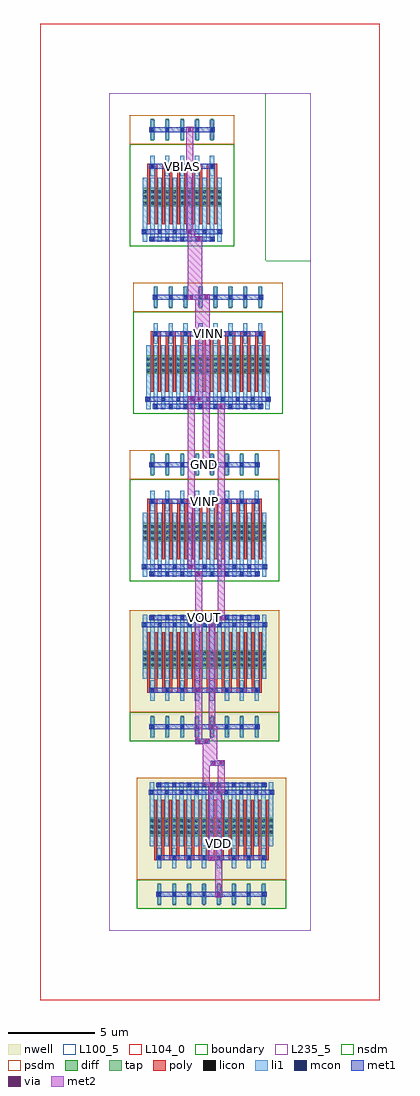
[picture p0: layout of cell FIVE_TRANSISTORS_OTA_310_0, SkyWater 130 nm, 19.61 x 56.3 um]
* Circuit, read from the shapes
.subckt FIVE_TRANSISTORS_OTA_310_0 GND VBIAS VDD VINN VINP VOUT
XM1 n1 VINP n2 GND sky130_fd_pr__nfet_01v8 w=1.05 l=0.15 m=16
XM2 n2 VBIAS GND GND sky130_fd_pr__nfet_01v8 w=1.05 l=0.15 m=10
XM3 VOUT VINN n2 GND sky130_fd_pr__nfet_01v8 w=1.05 l=0.15 m=16
XM4 VOUT n1 VDD VDD sky130_fd_pr__pfet_01v8 w=1.05 l=0.15 m=16
XM5 n1 n1 VDD VDD sky130_fd_pr__pfet_01v8 w=1.05 l=0.15 m=16
.ends

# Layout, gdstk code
import gdstk
lib = gdstk.Library(unit=1e-6, precision=1e-09)
def R(c, l, rs):  # rectangles x0, y0, x1, y1
    for r in rs: c.add(gdstk.rectangle(r[:2], r[2:], *l))
def A(c, l, x, y, w, h, nx, ny, dx, dy):  # array of equal rectangles
    R(c, l, [(x+i*dx, y+j*dy, x+i*dx+w, y+j*dy+h) for i in range(nx) for j in range(ny)])
def P(c, l, *ps):  # polygons
    for p in ps: c.add(gdstk.Polygon(p, *l))
nwell = (64, 20)
diff = (65, 20)
tap = (65, 44)
poly = (66, 20)
licon = (66, 44)
li1 = (67, 20)
mcon = (67, 44)
met1 = (68, 20)
via = (68, 44)
met2 = (69, 20)
nsdm = (93, 44)
psdm = (94, 20)
L100_5 = (100, 5)
L104_0 = (104, 0)
boundary = (235, 4)
L235_5 = (235, 5)

dcl_pmos_s_17530687_x8_y = lib.new_cell('DCL_PMOS_S_17530687_X8_Y1_1746753567')
R(dcl_pmos_s_17530687_x8_y, nwell, [(1.59,0.84,10.19,8.4)])
R(dcl_pmos_s_17530687_x8_y, diff, [(2.325,3.15,9.455,4.2)])
A(dcl_pmos_s_17530687_x8_y, tap, 2.795, 6.915, 0.17, 1.29, 8, 1, 0.86, 0)
A(dcl_pmos_s_17530687_x8_y, poly, 2.59, 2.1, 0.15, 3.36, 16, 1, 0.43, 0)
A(dcl_pmos_s_17530687_x8_y, poly, 2.59, 5.325, 0.58, 0.27, 8, 1, 0.86, 0)
A(dcl_pmos_s_17530687_x8_y, licon, 2.365, 3.23, 0.17, 0.17, 3, 3, 0.43, 0.34)
A(dcl_pmos_s_17530687_x8_y, licon, 3.225, 3.23, 0.17, 0.17, 3, 3, 0.43, 0.34)
A(dcl_pmos_s_17530687_x8_y, licon, 4.085, 3.23, 0.17, 0.17, 3, 3, 0.43, 0.34)
A(dcl_pmos_s_17530687_x8_y, licon, 4.945, 3.23, 0.17, 0.17, 3, 3, 0.43, 0.34)
A(dcl_pmos_s_17530687_x8_y, licon, 5.805, 3.23, 0.17, 0.17, 3, 3, 0.43, 0.34)
A(dcl_pmos_s_17530687_x8_y, licon, 6.665, 3.23, 0.17, 0.17, 3, 3, 0.43, 0.34)
A(dcl_pmos_s_17530687_x8_y, licon, 7.525, 3.23, 0.17, 0.17, 3, 3, 0.43, 0.34)
A(dcl_pmos_s_17530687_x8_y, licon, 8.385, 3.23, 0.17, 0.17, 3, 3, 0.43, 0.34)
A(dcl_pmos_s_17530687_x8_y, licon, 2.795, 5.375, 0.17, 0.17, 8, 2, 0.86, 2.1)
A(dcl_pmos_s_17530687_x8_y, li1, 2.325, 1.09, 0.25, 3.7, 17, 1, 0.43, 0)
A(dcl_pmos_s_17530687_x8_y, li1, 2.755, 4.87, 0.25, 1.18, 8, 2, 0.86, 2.1)
A(dcl_pmos_s_17530687_x8_y, mcon, 2.795, 1.175, 0.17, 0.17, 8, 2, 0.86, 4.2)
A(dcl_pmos_s_17530687_x8_y, mcon, 2.365, 1.595, 0.17, 0.17, 9, 1, 0.86, 0)
A(dcl_pmos_s_17530687_x8_y, mcon, 2.795, 7.475, 0.17, 0.17, 8, 1, 0.86, 0)
R(dcl_pmos_s_17530687_x8_y, met1, [(2.71,1.12,9.07,1.4), (2.28,1.54,9.5,1.82), (2.71,5.32,9.07,5.6), (2.71,7.42,9.07,7.7)])
R(dcl_pmos_s_17530687_x8_y, via, [(5.815,1.185,5.965,1.335), (6.245,1.605,6.395,1.755), (5.815,5.385,5.965,5.535), (6.245,7.485,6.395,7.635)])
R(dcl_pmos_s_17530687_x8_y, met2, [(5.69,1.1,6.09,5.62), (6.12,1.52,6.52,7.72)])
R(dcl_pmos_s_17530687_x8_y, nsdm, [(1.59,6.72,10.19,8.4)])
R(dcl_pmos_s_17530687_x8_y, psdm, [(1.59,0.84,10.19,6.72)])
R(dcl_pmos_s_17530687_x8_y, L100_5, [(0,0,11.61,9.66)])
R(dcl_pmos_s_17530687_x8_y, boundary, [(0,0,11.61,9.66)])

nmos_s_52209288_x5_y1_17 = lib.new_cell('NMOS_S_52209288_X5_Y1_1746753570')
R(nmos_s_52209288_x5_y1_17, diff, [(1.925,3.15,6.475,4.2)])
A(nmos_s_52209288_x5_y1_17, tap, 2.395, 6.915, 0.17, 1.29, 5, 1, 0.86, 0)
A(nmos_s_52209288_x5_y1_17, poly, 2.19, 2.1, 0.15, 3.36, 10, 1, 0.43, 0)
A(nmos_s_52209288_x5_y1_17, poly, 2.19, 5.325, 0.58, 0.27, 5, 1, 0.86, 0)
A(nmos_s_52209288_x5_y1_17, licon, 1.965, 3.23, 0.17, 0.17, 3, 3, 0.43, 0.34)
A(nmos_s_52209288_x5_y1_17, licon, 2.825, 3.23, 0.17, 0.17, 3, 3, 0.43, 0.34)
A(nmos_s_52209288_x5_y1_17, licon, 3.685, 3.23, 0.17, 0.17, 3, 3, 0.43, 0.34)
A(nmos_s_52209288_x5_y1_17, licon, 4.545, 3.23, 0.17, 0.17, 3, 3, 0.43, 0.34)
A(nmos_s_52209288_x5_y1_17, licon, 5.405, 3.23, 0.17, 0.17, 3, 3, 0.43, 0.34)
A(nmos_s_52209288_x5_y1_17, licon, 2.395, 5.375, 0.17, 0.17, 5, 2, 0.86, 2.1)
A(nmos_s_52209288_x5_y1_17, li1, 1.925, 1.09, 0.25, 3.7, 11, 1, 0.43, 0)
A(nmos_s_52209288_x5_y1_17, li1, 2.355, 4.87, 0.25, 1.18, 5, 2, 0.86, 2.1)
A(nmos_s_52209288_x5_y1_17, mcon, 2.395, 1.175, 0.17, 0.17, 5, 2, 0.86, 4.2)
A(nmos_s_52209288_x5_y1_17, mcon, 1.965, 1.595, 0.17, 0.17, 6, 1, 0.86, 0)
A(nmos_s_52209288_x5_y1_17, mcon, 2.395, 7.475, 0.17, 0.17, 5, 1, 0.86, 0)
R(nmos_s_52209288_x5_y1_17, met1, [(2.31,1.12,6.09,1.4), (1.88,1.54,6.52,1.82), (2.31,5.32,6.09,5.6), (2.31,7.42,6.09,7.7)])
R(nmos_s_52209288_x5_y1_17, via, [(4.555,1.605,4.705,1.755), (4.555,7.485,4.705,7.635)])
R(nmos_s_52209288_x5_y1_17, met2, [(4.43,1.52,4.83,7.72)])
R(nmos_s_52209288_x5_y1_17, nsdm, [(1.19,0.84,7.21,6.72)])
R(nmos_s_52209288_x5_y1_17, psdm, [(1.19,6.72,7.21,8.4)])
R(nmos_s_52209288_x5_y1_17, L100_5, [(0,0,9.03,9.66)])
R(nmos_s_52209288_x5_y1_17, boundary, [(0,0,9.03,9.66)])

pmos_s_93182587_x8_y1_17 = lib.new_cell('PMOS_S_93182587_X8_Y1_1746753571')
R(pmos_s_93182587_x8_y1_17, nwell, [(1.19,0.84,9.79,8.4)])
R(pmos_s_93182587_x8_y1_17, diff, [(1.925,3.15,9.055,4.2)])
A(pmos_s_93182587_x8_y1_17, tap, 2.395, 6.915, 0.17, 1.29, 8, 1, 0.86, 0)
A(pmos_s_93182587_x8_y1_17, poly, 2.19, 2.1, 0.15, 3.36, 16, 1, 0.43, 0)
A(pmos_s_93182587_x8_y1_17, poly, 2.19, 5.325, 0.58, 0.27, 8, 1, 0.86, 0)
A(pmos_s_93182587_x8_y1_17, licon, 1.965, 3.23, 0.17, 0.17, 3, 3, 0.43, 0.34)
A(pmos_s_93182587_x8_y1_17, licon, 2.825, 3.23, 0.17, 0.17, 3, 3, 0.43, 0.34)
A(pmos_s_93182587_x8_y1_17, licon, 3.685, 3.23, 0.17, 0.17, 3, 3, 0.43, 0.34)
A(pmos_s_93182587_x8_y1_17, licon, 4.545, 3.23, 0.17, 0.17, 3, 3, 0.43, 0.34)
A(pmos_s_93182587_x8_y1_17, licon, 5.405, 3.23, 0.17, 0.17, 3, 3, 0.43, 0.34)
A(pmos_s_93182587_x8_y1_17, licon, 6.265, 3.23, 0.17, 0.17, 3, 3, 0.43, 0.34)
A(pmos_s_93182587_x8_y1_17, licon, 7.125, 3.23, 0.17, 0.17, 3, 3, 0.43, 0.34)
A(pmos_s_93182587_x8_y1_17, licon, 7.985, 3.23, 0.17, 0.17, 3, 3, 0.43, 0.34)
A(pmos_s_93182587_x8_y1_17, licon, 2.395, 5.375, 0.17, 0.17, 8, 2, 0.86, 2.1)
A(pmos_s_93182587_x8_y1_17, li1, 1.925, 1.09, 0.25, 3.7, 17, 1, 0.43, 0)
A(pmos_s_93182587_x8_y1_17, li1, 2.355, 4.87, 0.25, 1.18, 8, 2, 0.86, 2.1)
A(pmos_s_93182587_x8_y1_17, mcon, 2.395, 1.175, 0.17, 0.17, 8, 2, 0.86, 4.2)
A(pmos_s_93182587_x8_y1_17, mcon, 1.965, 1.595, 0.17, 0.17, 9, 1, 0.86, 0)
A(pmos_s_93182587_x8_y1_17, mcon, 2.395, 7.475, 0.17, 0.17, 8, 1, 0.86, 0)
R(pmos_s_93182587_x8_y1_17, met1, [(2.31,1.12,8.67,1.4), (1.88,1.54,9.1,1.82), (2.31,5.32,8.67,5.6), (2.31,7.42,8.67,7.7)])
R(pmos_s_93182587_x8_y1_17, via, [(5.845,1.605,5.995,1.755), (5.845,7.485,5.995,7.635)])
R(pmos_s_93182587_x8_y1_17, met2, [(5.72,1.52,6.12,7.72)])
R(pmos_s_93182587_x8_y1_17, nsdm, [(1.19,6.72,9.79,8.4)])
R(pmos_s_93182587_x8_y1_17, psdm, [(1.19,0.84,9.79,6.72)])
R(pmos_s_93182587_x8_y1_17, L100_5, [(0,0,11.61,9.66)])
R(pmos_s_93182587_x8_y1_17, boundary, [(0,0,11.61,9.66)])

nmos_4t_3160949_x8_y1_17 = lib.new_cell('NMOS_4T_3160949_X8_Y1_1746753569')
R(nmos_4t_3160949_x8_y1_17, diff, [(2.125,3.15,9.255,4.2)])
A(nmos_4t_3160949_x8_y1_17, tap, 2.595, 6.915, 0.17, 1.29, 8, 1, 0.86, 0)
A(nmos_4t_3160949_x8_y1_17, poly, 2.39, 2.1, 0.15, 3.36, 16, 1, 0.43, 0)
A(nmos_4t_3160949_x8_y1_17, poly, 2.39, 5.325, 0.58, 0.27, 8, 1, 0.86, 0)
A(nmos_4t_3160949_x8_y1_17, licon, 2.165, 3.23, 0.17, 0.17, 3, 3, 0.43, 0.34)
A(nmos_4t_3160949_x8_y1_17, licon, 3.025, 3.23, 0.17, 0.17, 3, 3, 0.43, 0.34)
A(nmos_4t_3160949_x8_y1_17, licon, 3.885, 3.23, 0.17, 0.17, 3, 3, 0.43, 0.34)
A(nmos_4t_3160949_x8_y1_17, licon, 4.745, 3.23, 0.17, 0.17, 3, 3, 0.43, 0.34)
A(nmos_4t_3160949_x8_y1_17, licon, 5.605, 3.23, 0.17, 0.17, 3, 3, 0.43, 0.34)
A(nmos_4t_3160949_x8_y1_17, licon, 6.465, 3.23, 0.17, 0.17, 3, 3, 0.43, 0.34)
A(nmos_4t_3160949_x8_y1_17, licon, 7.325, 3.23, 0.17, 0.17, 3, 3, 0.43, 0.34)
A(nmos_4t_3160949_x8_y1_17, licon, 8.185, 3.23, 0.17, 0.17, 3, 3, 0.43, 0.34)
A(nmos_4t_3160949_x8_y1_17, licon, 2.595, 5.375, 0.17, 0.17, 8, 2, 0.86, 2.1)
A(nmos_4t_3160949_x8_y1_17, li1, 2.125, 1.09, 0.25, 3.7, 17, 1, 0.43, 0)
A(nmos_4t_3160949_x8_y1_17, li1, 2.555, 4.87, 0.25, 1.18, 8, 2, 0.86, 2.1)
A(nmos_4t_3160949_x8_y1_17, mcon, 2.595, 1.175, 0.17, 0.17, 8, 2, 0.86, 4.2)
A(nmos_4t_3160949_x8_y1_17, mcon, 2.165, 1.595, 0.17, 0.17, 9, 1, 0.86, 0)
A(nmos_4t_3160949_x8_y1_17, mcon, 2.595, 7.475, 0.17, 0.17, 8, 1, 0.86, 0)
R(nmos_4t_3160949_x8_y1_17, met1, [(2.51,1.12,8.87,1.4), (2.08,1.54,9.3,1.82), (2.51,5.32,8.87,5.6), (2.51,7.42,8.87,7.7)])
R(nmos_4t_3160949_x8_y1_17, nsdm, [(1.39,0.84,9.99,6.72)])
R(nmos_4t_3160949_x8_y1_17, psdm, [(1.39,6.72,9.99,8.4)])
R(nmos_4t_3160949_x8_y1_17, L100_5, [(0,0,11.61,9.66)])
R(nmos_4t_3160949_x8_y1_17, boundary, [(0,0,11.61,9.66)])

nmos_4t_21140221_x8_y1_1 = lib.new_cell('NMOS_4T_21140221_X8_Y1_1746753568')
R(nmos_4t_21140221_x8_y1_1, diff, [(1.925,3.15,9.055,4.2)])
A(nmos_4t_21140221_x8_y1_1, tap, 2.395, 6.915, 0.17, 1.29, 8, 1, 0.86, 0)
A(nmos_4t_21140221_x8_y1_1, poly, 2.19, 2.1, 0.15, 3.36, 16, 1, 0.43, 0)
A(nmos_4t_21140221_x8_y1_1, poly, 2.19, 5.325, 0.58, 0.27, 8, 1, 0.86, 0)
A(nmos_4t_21140221_x8_y1_1, licon, 1.965, 3.23, 0.17, 0.17, 3, 3, 0.43, 0.34)
A(nmos_4t_21140221_x8_y1_1, licon, 2.825, 3.23, 0.17, 0.17, 3, 3, 0.43, 0.34)
A(nmos_4t_21140221_x8_y1_1, licon, 3.685, 3.23, 0.17, 0.17, 3, 3, 0.43, 0.34)
A(nmos_4t_21140221_x8_y1_1, licon, 4.545, 3.23, 0.17, 0.17, 3, 3, 0.43, 0.34)
A(nmos_4t_21140221_x8_y1_1, licon, 5.405, 3.23, 0.17, 0.17, 3, 3, 0.43, 0.34)
A(nmos_4t_21140221_x8_y1_1, licon, 6.265, 3.23, 0.17, 0.17, 3, 3, 0.43, 0.34)
A(nmos_4t_21140221_x8_y1_1, licon, 7.125, 3.23, 0.17, 0.17, 3, 3, 0.43, 0.34)
A(nmos_4t_21140221_x8_y1_1, licon, 7.985, 3.23, 0.17, 0.17, 3, 3, 0.43, 0.34)
A(nmos_4t_21140221_x8_y1_1, licon, 2.395, 5.375, 0.17, 0.17, 8, 2, 0.86, 2.1)
A(nmos_4t_21140221_x8_y1_1, li1, 1.925, 1.09, 0.25, 3.7, 17, 1, 0.43, 0)
A(nmos_4t_21140221_x8_y1_1, li1, 2.355, 4.87, 0.25, 1.18, 8, 2, 0.86, 2.1)
A(nmos_4t_21140221_x8_y1_1, mcon, 2.395, 1.175, 0.17, 0.17, 8, 2, 0.86, 4.2)
A(nmos_4t_21140221_x8_y1_1, mcon, 1.965, 1.595, 0.17, 0.17, 9, 1, 0.86, 0)
A(nmos_4t_21140221_x8_y1_1, mcon, 2.395, 7.475, 0.17, 0.17, 8, 1, 0.86, 0)
R(nmos_4t_21140221_x8_y1_1, met1, [(2.31,1.12,8.67,1.4), (1.88,1.54,9.1,1.82), (2.31,5.32,8.67,5.6), (2.31,7.42,8.67,7.7)])
R(nmos_4t_21140221_x8_y1_1, nsdm, [(1.19,0.84,9.79,6.72)])
R(nmos_4t_21140221_x8_y1_1, psdm, [(1.19,6.72,9.79,8.4)])
R(nmos_4t_21140221_x8_y1_1, L100_5, [(0,0,11.61,9.66)])
R(nmos_4t_21140221_x8_y1_1, boundary, [(0,0,11.61,9.66)])

five_transistors_ota_310 = lib.new_cell('FIVE_TRANSISTORS_OTA_310_0')
R(five_transistors_ota_310, met1, [(5.86,9.52,6.18,9.8), (5.86,9.52,6.18,9.8), (6.02,9.52,6.45,9.8), (6.29,9.52,6.61,9.8), (6.29,9.52,6.61,9.8), (5,10.78,5.32,11.06), (5,10.78,5.32,11.06), (5,10.78,5.32,11.06), (5,10.78,5.32,11.06), (5.16,10.78,5.59,11.06), (5.43,10.78,5.75,11.06), (5.43,10.78,5.75,11.06), (5.43,10.78,5.75,11.06), (5.43,10.78,5.75,11.06), (5,13.72,5.32,14), (5,13.72,5.32,14), (5,13.72,5.32,14), (5,13.72,5.32,14), (6.29,17.92,6.61,18.2), (6.29,17.92,6.61,18.2), (5,20.44,5.32,20.72), (5,20.44,5.32,20.72), (4.57,20.86,4.89,21.14), (4.57,20.86,4.89,21.14), (4.57,20.86,4.89,21.14), (4.57,20.86,4.89,21.14), (5.43,26.74,5.75,27.02), (5.43,26.74,5.75,27.02), (5.43,26.74,5.75,27.02), (5.43,26.74,5.75,27.02), (6.29,30.1,6.61,30.38), (6.29,30.1,6.61,30.38), (4.57,30.52,4.89,30.8), (4.57,30.52,4.89,30.8), (4.57,30.52,4.89,30.8), (4.57,30.52,4.89,30.8), (5,30.52,5.32,30.8), (5,30.52,5.32,30.8), (4.57,36.4,4.89,36.68), (4.57,36.4,4.89,36.68), (5.43,36.4,5.75,36.68), (5.43,36.4,5.75,36.68), (5.43,36.4,5.75,36.68), (5.43,36.4,5.75,36.68), (5,39.76,5.32,40.04), (5,39.76,5.32,40.04)])
P(five_transistors_ota_310, met1, [(0,0),(0,0),(0,0),(0,0)],
  [(0,0),(0,0),(0,0),(0,0)],
  [(0,0),(0,0),(0,0),(0,0)],
  [(0,0),(0,0),(0,0),(0,0)],
  [(0,0),(0,0),(0,0),(0,0)],
  [(0,0),(0,0),(0,0),(0,0)],
  [(0,0),(0,0),(0,0),(0,0)],
  [(0,0),(0,0),(0,0),(0,0)],
  [(0,0),(0,0),(0,0),(0,0)],
  [(0,0),(0,0),(0,0),(0,0)],
  [(0,0),(0,0),(0,0),(0,0)],
  [(0,0),(0,0),(0,0),(0,0)],
  [(0,0),(0,0),(0,0),(0,0)],
  [(0,0),(0,0),(0,0),(0,0)],
  [(0,0),(0,0),(0,0),(0,0)],
  [(0,0),(0,0),(0,0),(0,0)],
  [(0,0),(0,0),(0,0),(0,0)])
R(five_transistors_ota_310, via, [(5.945,9.585,6.095,9.735), (5.945,9.585,6.095,9.735), (6.375,9.585,6.525,9.735), (6.375,9.585,6.525,9.735), (5.085,10.845,5.235,10.995), (5.085,10.845,5.235,10.995), (5.085,10.845,5.235,10.995), (5.085,10.845,5.235,10.995), (5.515,10.845,5.665,10.995), (5.515,10.845,5.665,10.995), (5.515,10.845,5.665,10.995), (5.515,10.845,5.665,10.995), (5.085,13.785,5.235,13.935), (5.085,13.785,5.235,13.935), (5.085,13.785,5.235,13.935), (5.085,13.785,5.235,13.935), (6.375,17.985,6.525,18.135), (6.375,17.985,6.525,18.135), (5.085,20.505,5.235,20.655), (5.085,20.505,5.235,20.655), (4.655,20.925,4.805,21.075), (4.655,20.925,4.805,21.075), (4.655,20.925,4.805,21.075), (4.655,20.925,4.805,21.075), (5.515,26.805,5.665,26.955), (5.515,26.805,5.665,26.955), (5.515,26.805,5.665,26.955), (5.515,26.805,5.665,26.955), (6.375,30.165,6.525,30.315), (6.375,30.165,6.525,30.315), (4.655,30.585,4.805,30.735), (4.655,30.585,4.805,30.735), (4.655,30.585,4.805,30.735), (4.655,30.585,4.805,30.735), (5.085,30.585,5.235,30.735), (5.085,30.585,5.235,30.735), (4.655,36.465,4.805,36.615), (4.655,36.465,4.805,36.615), (5.515,36.465,5.665,36.615), (5.515,36.465,5.665,36.615), (5.515,36.465,5.665,36.615), (5.515,36.465,5.665,36.615), (5.085,39.825,5.235,39.975), (5.085,39.825,5.235,39.975)])
R(five_transistors_ota_310, met2, [(6.25,7.98,6.65,9.66), (5.39,8.4,5.79,10.92), (5.82,9.5,6.22,9.82), (5.82,9.5,6.22,9.82), (6.25,9.5,6.65,9.82), (6.25,9.5,6.65,9.82), (5.82,9.66,6.22,11.76), (4.96,10.76,5.36,11.08), (4.96,10.76,5.36,11.08), (4.96,10.76,5.36,11.08), (4.96,10.76,5.36,11.08), (5.39,10.76,5.79,11.08), (5.39,10.76,5.79,11.08), (5.39,10.76,5.79,11.08), (5.39,10.76,5.79,11.08), (4.96,10.92,5.36,13.86), (4.96,13.7,5.36,14.02), (4.96,13.7,5.36,14.02), (4.96,13.7,5.36,14.02), (4.96,13.7,5.36,14.02), (4.96,13.86,5.36,20.58), (6.25,17.9,6.65,18.22), (6.25,17.9,6.65,18.22), (6.25,18.06,6.65,30.24), (4.96,20.42,5.36,20.74), (4.96,20.42,5.36,20.74), (4.53,20.84,4.93,21.16), (4.53,20.84,4.93,21.16), (4.53,20.84,4.93,21.16), (4.53,20.84,4.93,21.16), (4.53,21,4.93,30.66), (5.39,26.72,5.79,27.04), (5.39,26.72,5.79,27.04), (5.39,26.72,5.79,27.04), (5.39,26.72,5.79,27.04), (5.39,26.88,5.79,36.54), (6.25,30.08,6.65,30.4), (6.25,30.08,6.65,30.4), (4.53,30.5,4.93,30.82), (4.53,30.5,4.93,30.82), (4.53,30.5,4.93,30.82), (4.53,30.5,4.93,30.82), (4.96,30.5,5.36,30.82), (4.96,30.5,5.36,30.82), (4.96,30.66,5.36,39.9), (4.53,36.38,4.93,36.7), (4.53,36.38,4.93,36.7), (5.39,36.38,5.79,36.7), (5.39,36.38,5.79,36.7), (5.39,36.38,5.79,36.7), (5.39,36.38,5.79,36.7), (4.53,36.54,4.93,40.32), (4.96,39.74,5.36,40.06), (4.96,39.74,5.36,40.06)])
P(five_transistors_ota_310, met2, [(0,0),(0,0),(0,0),(0,0)],
  [(0,0),(0,0),(0,0),(0,0)],
  [(0,0),(0,0),(0,0),(0,0)],
  [(0,0),(0,0),(0,0),(0,0)],
  [(0,0),(0,0),(0,0),(0,0)])
R(five_transistors_ota_310, L104_0, [(-4,-4,15.61,52.3)])
R(five_transistors_ota_310, L235_5, [(0,0,11.61,48.3)])
five_transistors_ota_310.add(gdstk.Reference(dcl_pmos_s_17530687_x8_y, (0,9.66), x_reflection=True))
five_transistors_ota_310.add(gdstk.Reference(nmos_s_52209288_x5_y1_17, (0,38.64)))
five_transistors_ota_310.add(gdstk.Reference(pmos_s_93182587_x8_y1_17, (0,19.32), x_reflection=True))
five_transistors_ota_310.add(gdstk.Reference(nmos_4t_3160949_x8_y1_17, (0,28.98)))
five_transistors_ota_310.add(gdstk.Reference(nmos_4t_21140221_x8_y1_1, (0,19.32)))
five_transistors_ota_310.add(gdstk.Label('VDD', (6.32,5.04), layer=69, texttype=5))
five_transistors_ota_310.add(gdstk.Label('VBIAS', (4.2,44.1), layer=68, texttype=5))
five_transistors_ota_310.add(gdstk.Label('GND', (5.49,26.88), layer=68, texttype=5))
five_transistors_ota_310.add(gdstk.Label('VOUT', (5.49,18.06), layer=68, texttype=5))
five_transistors_ota_310.add(gdstk.Label('VINN', (5.69,34.44), layer=68, texttype=5))
five_transistors_ota_310.add(gdstk.Label('VINP', (5.49,24.78), layer=68, texttype=5))

lib.write_gds('FIVE_TRANSISTORS_OTA_310_0.gds')
